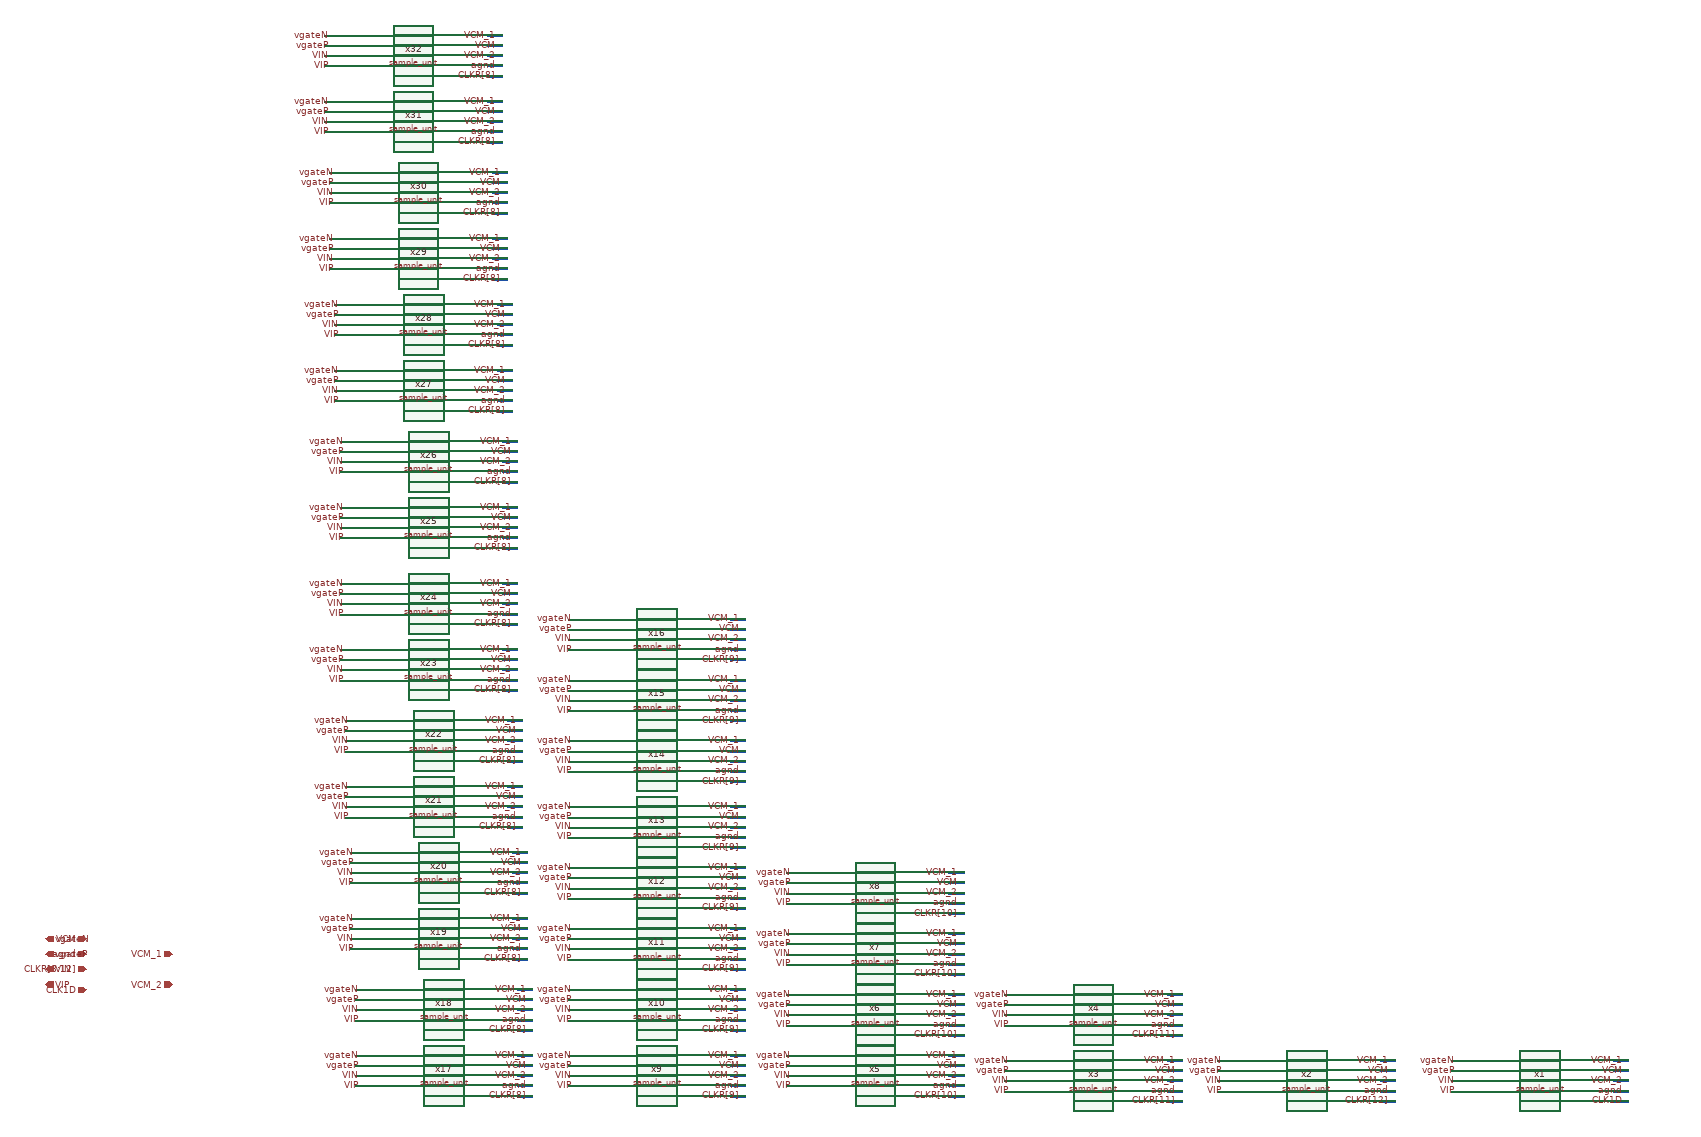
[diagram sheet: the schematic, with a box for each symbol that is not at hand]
v {xschem version=3.1.0 file_version=1.2
}
G {}
K {}
V {}
S {}
E {}
N 200 -80 220 -80 {
lab=VIN}
N 200 -60 220 -60 {
lab=VIP}
N 200 -100 220 -100 {
lab=vgateP}
N 200 -120 220 -120 {
lab=vgateN}
N 520 -120 550 -120 {
lab=VCM_1}
N 520 -100 550 -100 {
lab=VCM}
N 520 -80 550 -80 {
lab=VCM_2}
N 520 -40 550 -40 {
lab=CLK1D}
N 520 -60 550 -60 {
lab=agnd}
N -260 -80 -240 -80 {
lab=VIN}
N -260 -60 -240 -60 {
lab=VIP}
N -260 -100 -240 -100 {
lab=vgateP}
N -260 -120 -240 -120 {
lab=vgateN}
N 60 -120 90 -120 {
lab=VCM_1}
N 60 -100 90 -100 {
lab=VCM}
N 60 -80 90 -80 {
lab=VCM_2}
N 60 -40 90 -40 {
lab=CLKR[12]}
N 60 -60 90 -60 {
lab=agnd}
N -680 -80 -660 -80 {
lab=VIN}
N -680 -60 -660 -60 {
lab=VIP}
N -680 -100 -660 -100 {
lab=vgateP}
N -680 -120 -660 -120 {
lab=vgateN}
N -360 -120 -330 -120 {
lab=VCM_1}
N -360 -100 -330 -100 {
lab=VCM}
N -360 -80 -330 -80 {
lab=VCM_2}
N -360 -40 -330 -40 {
lab=CLKR[11]}
N -360 -60 -330 -60 {
lab=agnd}
N -680 -210 -660 -210 {
lab=VIN}
N -680 -190 -660 -190 {
lab=VIP}
N -680 -230 -660 -230 {
lab=vgateP}
N -680 -250 -660 -250 {
lab=vgateN}
N -360 -250 -330 -250 {
lab=VCM_1}
N -360 -230 -330 -230 {
lab=VCM}
N -360 -210 -330 -210 {
lab=VCM_2}
N -360 -170 -330 -170 {
lab=CLKR[11]}
N -360 -190 -330 -190 {
lab=agnd}
N -1110 -90 -1090 -90 {
lab=VIN}
N -1110 -70 -1090 -70 {
lab=VIP}
N -1110 -110 -1090 -110 {
lab=vgateP}
N -1110 -130 -1090 -130 {
lab=vgateN}
N -790 -130 -760 -130 {
lab=VCM_1}
N -790 -110 -760 -110 {
lab=VCM}
N -790 -90 -760 -90 {
lab=VCM_2}
N -790 -50 -760 -50 {
lab=CLKR[10]}
N -790 -70 -760 -70 {
lab=agnd}
N -1110 -210 -1090 -210 {
lab=VIN}
N -1110 -190 -1090 -190 {
lab=VIP}
N -1110 -230 -1090 -230 {
lab=vgateP}
N -1110 -250 -1090 -250 {
lab=vgateN}
N -790 -250 -760 -250 {
lab=VCM_1}
N -790 -230 -760 -230 {
lab=VCM}
N -790 -210 -760 -210 {
lab=VCM_2}
N -790 -170 -760 -170 {
lab=CLKR[10]}
N -790 -190 -760 -190 {
lab=agnd}
N -1110 -330 -1090 -330 {
lab=VIN}
N -1110 -310 -1090 -310 {
lab=VIP}
N -1110 -350 -1090 -350 {
lab=vgateP}
N -1110 -370 -1090 -370 {
lab=vgateN}
N -790 -370 -760 -370 {
lab=VCM_1}
N -790 -350 -760 -350 {
lab=VCM}
N -790 -330 -760 -330 {
lab=VCM_2}
N -790 -290 -760 -290 {
lab=CLKR[10]}
N -790 -310 -760 -310 {
lab=agnd}
N -1110 -450 -1090 -450 {
lab=VIN}
N -1110 -430 -1090 -430 {
lab=VIP}
N -1110 -470 -1090 -470 {
lab=vgateP}
N -1110 -490 -1090 -490 {
lab=vgateN}
N -790 -490 -760 -490 {
lab=VCM_1}
N -790 -470 -760 -470 {
lab=VCM}
N -790 -450 -760 -450 {
lab=VCM_2}
N -790 -410 -760 -410 {
lab=CLKR[10]}
N -790 -430 -760 -430 {
lab=agnd}
N -1540 -90 -1520 -90 {
lab=VIN}
N -1540 -70 -1520 -70 {
lab=VIP}
N -1540 -110 -1520 -110 {
lab=vgateP}
N -1540 -130 -1520 -130 {
lab=vgateN}
N -1220 -130 -1190 -130 {
lab=VCM_1}
N -1220 -110 -1190 -110 {
lab=VCM}
N -1220 -90 -1190 -90 {
lab=VCM_2}
N -1220 -50 -1190 -50 {
lab=CLKR[10]}
N -1220 -70 -1190 -70 {
lab=agnd}
N -1540 -220 -1520 -220 {
lab=VIN}
N -1540 -200 -1520 -200 {
lab=VIP}
N -1540 -240 -1520 -240 {
lab=vgateP}
N -1540 -260 -1520 -260 {
lab=vgateN}
N -1220 -260 -1190 -260 {
lab=VCM_1}
N -1220 -240 -1190 -240 {
lab=VCM}
N -1220 -220 -1190 -220 {
lab=VCM_2}
N -1220 -180 -1190 -180 {
lab=CLKR[10]}
N -1220 -200 -1190 -200 {
lab=agnd}
N -1540 -340 -1520 -340 {
lab=VIN}
N -1540 -320 -1520 -320 {
lab=VIP}
N -1540 -360 -1520 -360 {
lab=vgateP}
N -1540 -380 -1520 -380 {
lab=vgateN}
N -1220 -380 -1190 -380 {
lab=VCM_1}
N -1220 -360 -1190 -360 {
lab=VCM}
N -1220 -340 -1190 -340 {
lab=VCM_2}
N -1220 -300 -1190 -300 {
lab=CLKR[10]}
N -1220 -320 -1190 -320 {
lab=agnd}
N -1540 -460 -1520 -460 {
lab=VIN}
N -1540 -440 -1520 -440 {
lab=VIP}
N -1540 -480 -1520 -480 {
lab=vgateP}
N -1540 -500 -1520 -500 {
lab=vgateN}
N -1220 -500 -1190 -500 {
lab=VCM_1}
N -1220 -480 -1190 -480 {
lab=VCM}
N -1220 -460 -1190 -460 {
lab=VCM_2}
N -1220 -420 -1190 -420 {
lab=CLKR[10]}
N -1220 -440 -1190 -440 {
lab=agnd}
N -1540 -580 -1520 -580 {
lab=VIN}
N -1540 -560 -1520 -560 {
lab=VIP}
N -1540 -600 -1520 -600 {
lab=vgateP}
N -1540 -620 -1520 -620 {
lab=vgateN}
N -1220 -620 -1190 -620 {
lab=VCM_1}
N -1220 -600 -1190 -600 {
lab=VCM}
N -1220 -580 -1190 -580 {
lab=VCM_2}
N -1220 -540 -1190 -540 {
lab=CLKR[10]}
N -1220 -560 -1190 -560 {
lab=agnd}
N -1540 -710 -1520 -710 {
lab=VIN}
N -1540 -690 -1520 -690 {
lab=VIP}
N -1540 -730 -1520 -730 {
lab=vgateP}
N -1540 -750 -1520 -750 {
lab=vgateN}
N -1220 -750 -1190 -750 {
lab=VCM_1}
N -1220 -730 -1190 -730 {
lab=VCM}
N -1220 -710 -1190 -710 {
lab=VCM_2}
N -1220 -670 -1190 -670 {
lab=CLKR[10]}
N -1220 -690 -1190 -690 {
lab=agnd}
N -1540 -830 -1520 -830 {
lab=VIN}
N -1540 -810 -1520 -810 {
lab=VIP}
N -1540 -850 -1520 -850 {
lab=vgateP}
N -1540 -870 -1520 -870 {
lab=vgateN}
N -1220 -870 -1190 -870 {
lab=VCM_1}
N -1220 -850 -1190 -850 {
lab=VCM}
N -1220 -830 -1190 -830 {
lab=VCM_2}
N -1220 -790 -1190 -790 {
lab=CLKR[10]}
N -1220 -810 -1190 -810 {
lab=agnd}
N -1540 -950 -1520 -950 {
lab=VIN}
N -1540 -930 -1520 -930 {
lab=VIP}
N -1540 -970 -1520 -970 {
lab=vgateP}
N -1540 -990 -1520 -990 {
lab=vgateN}
N -1220 -990 -1190 -990 {
lab=VCM_1}
N -1220 -970 -1190 -970 {
lab=VCM}
N -1220 -950 -1190 -950 {
lab=VCM_2}
N -1220 -910 -1190 -910 {
lab=CLKR[10]}
N -1220 -930 -1190 -930 {
lab=agnd}
N -1960 -90 -1940 -90 {
lab=VIN}
N -1960 -70 -1940 -70 {
lab=VIP}
N -1960 -110 -1940 -110 {
lab=vgateP}
N -1960 -130 -1940 -130 {
lab=vgateN}
N -1640 -130 -1610 -130 {
lab=VCM_1}
N -1640 -110 -1610 -110 {
lab=VCM}
N -1640 -90 -1610 -90 {
lab=VCM_2}
N -1640 -50 -1610 -50 {
lab=CLKR[10]}
N -1640 -70 -1610 -70 {
lab=agnd}
N -1960 -220 -1940 -220 {
lab=VIN}
N -1960 -200 -1940 -200 {
lab=VIP}
N -1960 -240 -1940 -240 {
lab=vgateP}
N -1960 -260 -1940 -260 {
lab=vgateN}
N -1640 -260 -1610 -260 {
lab=VCM_1}
N -1640 -240 -1610 -240 {
lab=VCM}
N -1640 -220 -1610 -220 {
lab=VCM_2}
N -1640 -180 -1610 -180 {
lab=CLKR[10]}
N -1640 -200 -1610 -200 {
lab=agnd}
N -1970 -360 -1950 -360 {
lab=VIN}
N -1970 -340 -1950 -340 {
lab=VIP}
N -1970 -380 -1950 -380 {
lab=vgateP}
N -1970 -400 -1950 -400 {
lab=vgateN}
N -1650 -400 -1620 -400 {
lab=VCM_1}
N -1650 -380 -1620 -380 {
lab=VCM}
N -1650 -360 -1620 -360 {
lab=VCM_2}
N -1650 -320 -1620 -320 {
lab=CLKR[10]}
N -1650 -340 -1620 -340 {
lab=agnd}
N -1970 -490 -1950 -490 {
lab=VIN}
N -1970 -470 -1950 -470 {
lab=VIP}
N -1970 -510 -1950 -510 {
lab=vgateP}
N -1970 -530 -1950 -530 {
lab=vgateN}
N -1650 -530 -1620 -530 {
lab=VCM_1}
N -1650 -510 -1620 -510 {
lab=VCM}
N -1650 -490 -1620 -490 {
lab=VCM_2}
N -1650 -450 -1620 -450 {
lab=CLKR[10]}
N -1650 -470 -1620 -470 {
lab=agnd}
N -1980 -620 -1960 -620 {
lab=VIN}
N -1980 -600 -1960 -600 {
lab=VIP}
N -1980 -640 -1960 -640 {
lab=vgateP}
N -1980 -660 -1960 -660 {
lab=vgateN}
N -1660 -660 -1630 -660 {
lab=VCM_1}
N -1660 -640 -1630 -640 {
lab=VCM}
N -1660 -620 -1630 -620 {
lab=VCM_2}
N -1660 -580 -1630 -580 {
lab=CLKR[10]}
N -1660 -600 -1630 -600 {
lab=agnd}
N -1980 -750 -1960 -750 {
lab=VIN}
N -1980 -730 -1960 -730 {
lab=VIP}
N -1980 -770 -1960 -770 {
lab=vgateP}
N -1980 -790 -1960 -790 {
lab=vgateN}
N -1660 -790 -1630 -790 {
lab=VCM_1}
N -1660 -770 -1630 -770 {
lab=VCM}
N -1660 -750 -1630 -750 {
lab=VCM_2}
N -1660 -710 -1630 -710 {
lab=CLKR[10]}
N -1660 -730 -1630 -730 {
lab=agnd}
N -1990 -890 -1970 -890 {
lab=VIN}
N -1990 -870 -1970 -870 {
lab=VIP}
N -1990 -910 -1970 -910 {
lab=vgateP}
N -1990 -930 -1970 -930 {
lab=vgateN}
N -1670 -930 -1640 -930 {
lab=VCM_1}
N -1670 -910 -1640 -910 {
lab=VCM}
N -1670 -890 -1640 -890 {
lab=VCM_2}
N -1670 -850 -1640 -850 {
lab=CLKR[10]}
N -1670 -870 -1640 -870 {
lab=agnd}
N -1990 -1020 -1970 -1020 {
lab=VIN}
N -1990 -1000 -1970 -1000 {
lab=VIP}
N -1990 -1040 -1970 -1040 {
lab=vgateP}
N -1990 -1060 -1970 -1060 {
lab=vgateN}
N -1670 -1060 -1640 -1060 {
lab=VCM_1}
N -1670 -1040 -1640 -1040 {
lab=VCM}
N -1670 -1020 -1640 -1020 {
lab=VCM_2}
N -1670 -980 -1640 -980 {
lab=CLKR[10]}
N -1670 -1000 -1640 -1000 {
lab=agnd}
N -1990 -1170 -1970 -1170 {
lab=VIN}
N -1990 -1150 -1970 -1150 {
lab=VIP}
N -1990 -1190 -1970 -1190 {
lab=vgateP}
N -1990 -1210 -1970 -1210 {
lab=vgateN}
N -1670 -1210 -1640 -1210 {
lab=VCM_1}
N -1670 -1190 -1640 -1190 {
lab=VCM}
N -1670 -1170 -1640 -1170 {
lab=VCM_2}
N -1670 -1130 -1640 -1130 {
lab=CLKR[10]}
N -1670 -1150 -1640 -1150 {
lab=agnd}
N -1990 -1300 -1970 -1300 {
lab=VIN}
N -1990 -1280 -1970 -1280 {
lab=VIP}
N -1990 -1320 -1970 -1320 {
lab=vgateP}
N -1990 -1340 -1970 -1340 {
lab=vgateN}
N -1670 -1340 -1640 -1340 {
lab=VCM_1}
N -1670 -1320 -1640 -1320 {
lab=VCM}
N -1670 -1300 -1640 -1300 {
lab=VCM_2}
N -1670 -1260 -1640 -1260 {
lab=CLKR[10]}
N -1670 -1280 -1640 -1280 {
lab=agnd}
N -2000 -1440 -1980 -1440 {
lab=VIN}
N -2000 -1420 -1980 -1420 {
lab=VIP}
N -2000 -1460 -1980 -1460 {
lab=vgateP}
N -2000 -1480 -1980 -1480 {
lab=vgateN}
N -1680 -1480 -1650 -1480 {
lab=VCM_1}
N -1680 -1460 -1650 -1460 {
lab=VCM}
N -1680 -1440 -1650 -1440 {
lab=VCM_2}
N -1680 -1400 -1650 -1400 {
lab=CLKR[10]}
N -1680 -1420 -1650 -1420 {
lab=agnd}
N -2000 -1570 -1980 -1570 {
lab=VIN}
N -2000 -1550 -1980 -1550 {
lab=VIP}
N -2000 -1590 -1980 -1590 {
lab=vgateP}
N -2000 -1610 -1980 -1610 {
lab=vgateN}
N -1680 -1610 -1650 -1610 {
lab=VCM_1}
N -1680 -1590 -1650 -1590 {
lab=VCM}
N -1680 -1570 -1650 -1570 {
lab=VCM_2}
N -1680 -1530 -1650 -1530 {
lab=CLKR[10]}
N -1680 -1550 -1650 -1550 {
lab=agnd}
N -2010 -1700 -1990 -1700 {
lab=VIN}
N -2010 -1680 -1990 -1680 {
lab=VIP}
N -2010 -1720 -1990 -1720 {
lab=vgateP}
N -2010 -1740 -1990 -1740 {
lab=vgateN}
N -1690 -1740 -1660 -1740 {
lab=VCM_1}
N -1690 -1720 -1660 -1720 {
lab=VCM}
N -1690 -1700 -1660 -1700 {
lab=VCM_2}
N -1690 -1660 -1660 -1660 {
lab=CLKR[10]}
N -1690 -1680 -1660 -1680 {
lab=agnd}
N -2010 -1830 -1990 -1830 {
lab=VIN}
N -2010 -1810 -1990 -1810 {
lab=VIP}
N -2010 -1850 -1990 -1850 {
lab=vgateP}
N -2010 -1870 -1990 -1870 {
lab=vgateN}
N -1690 -1870 -1660 -1870 {
lab=VCM_1}
N -1690 -1850 -1660 -1850 {
lab=VCM}
N -1690 -1830 -1660 -1830 {
lab=VCM_2}
N -1690 -1790 -1660 -1790 {
lab=CLKR[10]}
N -1690 -1810 -1660 -1810 {
lab=agnd}
N -2020 -1970 -2000 -1970 {
lab=VIN}
N -2020 -1950 -2000 -1950 {
lab=VIP}
N -2020 -1990 -2000 -1990 {
lab=vgateP}
N -2020 -2010 -2000 -2010 {
lab=vgateN}
N -1700 -2010 -1670 -2010 {
lab=VCM_1}
N -1700 -1990 -1670 -1990 {
lab=VCM}
N -1700 -1970 -1670 -1970 {
lab=VCM_2}
N -1700 -1930 -1670 -1930 {
lab=CLKR[10]}
N -1700 -1950 -1670 -1950 {
lab=agnd}
N -2020 -2100 -2000 -2100 {
lab=VIN}
N -2020 -2080 -2000 -2080 {
lab=VIP}
N -2020 -2120 -2000 -2120 {
lab=vgateP}
N -2020 -2140 -2000 -2140 {
lab=vgateN}
N -1700 -2140 -1670 -2140 {
lab=VCM_1}
N -1700 -2120 -1670 -2120 {
lab=VCM}
N -1700 -2100 -1670 -2100 {
lab=VCM_2}
N -1700 -2060 -1670 -2060 {
lab=CLKR[10]}
N -1700 -2080 -1670 -2080 {
lab=agnd}
C {/home/yihengfu/openmpw/tools-dev/sample_unit.sym} 370 -80 0 0 {name=x1}
C {lab_pin.sym} 540 -120 0 0 {name=p1 sig_type=std_logic lab=VCM_1}
C {lab_pin.sym} 540 -100 0 0 {name=p2 sig_type=std_logic lab=VCM}
C {lab_pin.sym} 540 -80 0 0 {name=p3 sig_type=std_logic lab=VCM_2}
C {lab_pin.sym} 540 -60 0 0 {name=p4 sig_type=std_logic lab=agnd}
C {lab_pin.sym} 540 -40 0 0 {name=p5 sig_type=std_logic lab=CLK1D}
C {lab_pin.sym} 210 -120 0 0 {name=p6 sig_type=std_logic lab=vgateN}
C {lab_pin.sym} 210 -100 0 0 {name=p7 sig_type=std_logic lab=vgateP}
C {lab_pin.sym} 210 -80 0 0 {name=p8 sig_type=std_logic lab=VIN}
C {lab_pin.sym} 210 -60 0 0 {name=p9 sig_type=std_logic lab=VIP}
C {/home/yihengfu/openmpw/tools-dev/sample_unit.sym} -90 -80 0 0 {name=x2}
C {lab_pin.sym} 80 -120 0 0 {name=p10 sig_type=std_logic lab=VCM_1}
C {lab_pin.sym} 80 -100 0 0 {name=p11 sig_type=std_logic lab=VCM}
C {lab_pin.sym} 80 -80 0 0 {name=p12 sig_type=std_logic lab=VCM_2}
C {lab_pin.sym} 80 -60 0 0 {name=p13 sig_type=std_logic lab=agnd}
C {lab_pin.sym} 80 -40 0 0 {name=p14 sig_type=std_logic lab=CLKR[12]}
C {lab_pin.sym} -250 -120 0 0 {name=p15 sig_type=std_logic lab=vgateN}
C {lab_pin.sym} -250 -100 0 0 {name=p16 sig_type=std_logic lab=vgateP}
C {lab_pin.sym} -250 -80 0 0 {name=p17 sig_type=std_logic lab=VIN}
C {lab_pin.sym} -250 -60 0 0 {name=p18 sig_type=std_logic lab=VIP}
C {/home/yihengfu/openmpw/tools-dev/sample_unit.sym} -510 -80 0 0 {name=x3}
C {lab_pin.sym} -340 -120 0 0 {name=p19 sig_type=std_logic lab=VCM_1}
C {lab_pin.sym} -340 -100 0 0 {name=p20 sig_type=std_logic lab=VCM}
C {lab_pin.sym} -340 -80 0 0 {name=p21 sig_type=std_logic lab=VCM_2}
C {lab_pin.sym} -340 -60 0 0 {name=p22 sig_type=std_logic lab=agnd}
C {lab_pin.sym} -340 -40 0 0 {name=p23 sig_type=std_logic lab=CLKR[11]}
C {lab_pin.sym} -670 -120 0 0 {name=p24 sig_type=std_logic lab=vgateN}
C {lab_pin.sym} -670 -100 0 0 {name=p25 sig_type=std_logic lab=vgateP}
C {lab_pin.sym} -670 -80 0 0 {name=p26 sig_type=std_logic lab=VIN}
C {lab_pin.sym} -670 -60 0 0 {name=p27 sig_type=std_logic lab=VIP}
C {/home/yihengfu/openmpw/tools-dev/sample_unit.sym} -510 -210 0 0 {name=x4}
C {lab_pin.sym} -340 -250 0 0 {name=p28 sig_type=std_logic lab=VCM_1}
C {lab_pin.sym} -340 -230 0 0 {name=p29 sig_type=std_logic lab=VCM}
C {lab_pin.sym} -340 -210 0 0 {name=p30 sig_type=std_logic lab=VCM_2}
C {lab_pin.sym} -340 -190 0 0 {name=p31 sig_type=std_logic lab=agnd}
C {lab_pin.sym} -340 -170 0 0 {name=p32 sig_type=std_logic lab=CLKR[11]}
C {lab_pin.sym} -670 -250 0 0 {name=p33 sig_type=std_logic lab=vgateN}
C {lab_pin.sym} -670 -230 0 0 {name=p34 sig_type=std_logic lab=vgateP}
C {lab_pin.sym} -670 -210 0 0 {name=p35 sig_type=std_logic lab=VIN}
C {lab_pin.sym} -670 -190 0 0 {name=p36 sig_type=std_logic lab=VIP}
C {/home/yihengfu/openmpw/tools-dev/sample_unit.sym} -940 -90 0 0 {name=x5}
C {lab_pin.sym} -770 -130 0 0 {name=p37 sig_type=std_logic lab=VCM_1}
C {lab_pin.sym} -770 -110 0 0 {name=p38 sig_type=std_logic lab=VCM}
C {lab_pin.sym} -770 -90 0 0 {name=p39 sig_type=std_logic lab=VCM_2}
C {lab_pin.sym} -770 -70 0 0 {name=p40 sig_type=std_logic lab=agnd}
C {lab_pin.sym} -770 -50 0 0 {name=p41 sig_type=std_logic lab=CLKR[10]}
C {lab_pin.sym} -1100 -130 0 0 {name=p42 sig_type=std_logic lab=vgateN}
C {lab_pin.sym} -1100 -110 0 0 {name=p43 sig_type=std_logic lab=vgateP}
C {lab_pin.sym} -1100 -90 0 0 {name=p44 sig_type=std_logic lab=VIN}
C {lab_pin.sym} -1100 -70 0 0 {name=p45 sig_type=std_logic lab=VIP}
C {/home/yihengfu/openmpw/tools-dev/sample_unit.sym} -940 -210 0 0 {name=x6}
C {lab_pin.sym} -770 -250 0 0 {name=p46 sig_type=std_logic lab=VCM_1}
C {lab_pin.sym} -770 -230 0 0 {name=p47 sig_type=std_logic lab=VCM}
C {lab_pin.sym} -770 -210 0 0 {name=p48 sig_type=std_logic lab=VCM_2}
C {lab_pin.sym} -770 -190 0 0 {name=p49 sig_type=std_logic lab=agnd}
C {lab_pin.sym} -770 -170 0 0 {name=p50 sig_type=std_logic lab=CLKR[10]}
C {lab_pin.sym} -1100 -250 0 0 {name=p51 sig_type=std_logic lab=vgateN}
C {lab_pin.sym} -1100 -230 0 0 {name=p52 sig_type=std_logic lab=vgateP}
C {lab_pin.sym} -1100 -210 0 0 {name=p53 sig_type=std_logic lab=VIN}
C {lab_pin.sym} -1100 -190 0 0 {name=p54 sig_type=std_logic lab=VIP}
C {/home/yihengfu/openmpw/tools-dev/sample_unit.sym} -940 -330 0 0 {name=x7}
C {lab_pin.sym} -770 -370 0 0 {name=p55 sig_type=std_logic lab=VCM_1}
C {lab_pin.sym} -770 -350 0 0 {name=p56 sig_type=std_logic lab=VCM}
C {lab_pin.sym} -770 -330 0 0 {name=p57 sig_type=std_logic lab=VCM_2}
C {lab_pin.sym} -770 -310 0 0 {name=p58 sig_type=std_logic lab=agnd}
C {lab_pin.sym} -770 -290 0 0 {name=p59 sig_type=std_logic lab=CLKR[10]}
C {lab_pin.sym} -1100 -370 0 0 {name=p60 sig_type=std_logic lab=vgateN}
C {lab_pin.sym} -1100 -350 0 0 {name=p61 sig_type=std_logic lab=vgateP}
C {lab_pin.sym} -1100 -330 0 0 {name=p62 sig_type=std_logic lab=VIN}
C {lab_pin.sym} -1100 -310 0 0 {name=p63 sig_type=std_logic lab=VIP}
C {/home/yihengfu/openmpw/tools-dev/sample_unit.sym} -940 -450 0 0 {name=x8}
C {lab_pin.sym} -770 -490 0 0 {name=p64 sig_type=std_logic lab=VCM_1}
C {lab_pin.sym} -770 -470 0 0 {name=p65 sig_type=std_logic lab=VCM}
C {lab_pin.sym} -770 -450 0 0 {name=p66 sig_type=std_logic lab=VCM_2}
C {lab_pin.sym} -770 -430 0 0 {name=p67 sig_type=std_logic lab=agnd}
C {lab_pin.sym} -770 -410 0 0 {name=p68 sig_type=std_logic lab=CLKR[10]}
C {lab_pin.sym} -1100 -490 0 0 {name=p69 sig_type=std_logic lab=vgateN}
C {lab_pin.sym} -1100 -470 0 0 {name=p70 sig_type=std_logic lab=vgateP}
C {lab_pin.sym} -1100 -450 0 0 {name=p71 sig_type=std_logic lab=VIN}
C {lab_pin.sym} -1100 -430 0 0 {name=p72 sig_type=std_logic lab=VIP}
C {/home/yihengfu/openmpw/tools-dev/sample_unit.sym} -1370 -90 0 0 {name=x9}
C {lab_pin.sym} -1200 -130 0 0 {name=p73 sig_type=std_logic lab=VCM_1}
C {lab_pin.sym} -1200 -110 0 0 {name=p74 sig_type=std_logic lab=VCM}
C {lab_pin.sym} -1200 -90 0 0 {name=p75 sig_type=std_logic lab=VCM_2}
C {lab_pin.sym} -1200 -70 0 0 {name=p76 sig_type=std_logic lab=agnd}
C {lab_pin.sym} -1200 -50 0 0 {name=p77 sig_type=std_logic lab=CLKR[9]}
C {lab_pin.sym} -1530 -130 0 0 {name=p78 sig_type=std_logic lab=vgateN}
C {lab_pin.sym} -1530 -110 0 0 {name=p79 sig_type=std_logic lab=vgateP}
C {lab_pin.sym} -1530 -90 0 0 {name=p80 sig_type=std_logic lab=VIN}
C {lab_pin.sym} -1530 -70 0 0 {name=p81 sig_type=std_logic lab=VIP}
C {/home/yihengfu/openmpw/tools-dev/sample_unit.sym} -1370 -220 0 0 {name=x10}
C {lab_pin.sym} -1200 -260 0 0 {name=p82 sig_type=std_logic lab=VCM_1}
C {lab_pin.sym} -1200 -240 0 0 {name=p83 sig_type=std_logic lab=VCM}
C {lab_pin.sym} -1200 -220 0 0 {name=p84 sig_type=std_logic lab=VCM_2}
C {lab_pin.sym} -1200 -200 0 0 {name=p85 sig_type=std_logic lab=agnd}
C {lab_pin.sym} -1200 -180 0 0 {name=p86 sig_type=std_logic lab=CLKR[9]}
C {lab_pin.sym} -1530 -260 0 0 {name=p87 sig_type=std_logic lab=vgateN}
C {lab_pin.sym} -1530 -240 0 0 {name=p88 sig_type=std_logic lab=vgateP}
C {lab_pin.sym} -1530 -220 0 0 {name=p89 sig_type=std_logic lab=VIN}
C {lab_pin.sym} -1530 -200 0 0 {name=p90 sig_type=std_logic lab=VIP}
C {/home/yihengfu/openmpw/tools-dev/sample_unit.sym} -1370 -340 0 0 {name=x11}
C {lab_pin.sym} -1200 -380 0 0 {name=p91 sig_type=std_logic lab=VCM_1}
C {lab_pin.sym} -1200 -360 0 0 {name=p92 sig_type=std_logic lab=VCM}
C {lab_pin.sym} -1200 -340 0 0 {name=p93 sig_type=std_logic lab=VCM_2}
C {lab_pin.sym} -1200 -320 0 0 {name=p94 sig_type=std_logic lab=agnd}
C {lab_pin.sym} -1200 -300 0 0 {name=p95 sig_type=std_logic lab=CLKR[9]}
C {lab_pin.sym} -1530 -380 0 0 {name=p96 sig_type=std_logic lab=vgateN}
C {lab_pin.sym} -1530 -360 0 0 {name=p97 sig_type=std_logic lab=vgateP}
C {lab_pin.sym} -1530 -340 0 0 {name=p98 sig_type=std_logic lab=VIN}
C {lab_pin.sym} -1530 -320 0 0 {name=p99 sig_type=std_logic lab=VIP}
C {/home/yihengfu/openmpw/tools-dev/sample_unit.sym} -1370 -460 0 0 {name=x12}
C {lab_pin.sym} -1200 -500 0 0 {name=p100 sig_type=std_logic lab=VCM_1}
C {lab_pin.sym} -1200 -480 0 0 {name=p101 sig_type=std_logic lab=VCM}
C {lab_pin.sym} -1200 -460 0 0 {name=p102 sig_type=std_logic lab=VCM_2}
C {lab_pin.sym} -1200 -440 0 0 {name=p103 sig_type=std_logic lab=agnd}
C {lab_pin.sym} -1200 -420 0 0 {name=p104 sig_type=std_logic lab=CLKR[9]}
C {lab_pin.sym} -1530 -500 0 0 {name=p105 sig_type=std_logic lab=vgateN}
C {lab_pin.sym} -1530 -480 0 0 {name=p106 sig_type=std_logic lab=vgateP}
C {lab_pin.sym} -1530 -460 0 0 {name=p107 sig_type=std_logic lab=VIN}
C {lab_pin.sym} -1530 -440 0 0 {name=p108 sig_type=std_logic lab=VIP}
C {/home/yihengfu/openmpw/tools-dev/sample_unit.sym} -1370 -580 0 0 {name=x13}
C {lab_pin.sym} -1200 -620 0 0 {name=p109 sig_type=std_logic lab=VCM_1}
C {lab_pin.sym} -1200 -600 0 0 {name=p110 sig_type=std_logic lab=VCM}
C {lab_pin.sym} -1200 -580 0 0 {name=p111 sig_type=std_logic lab=VCM_2}
C {lab_pin.sym} -1200 -560 0 0 {name=p112 sig_type=std_logic lab=agnd}
C {lab_pin.sym} -1200 -540 0 0 {name=p113 sig_type=std_logic lab=CLKR[9]}
C {lab_pin.sym} -1530 -620 0 0 {name=p114 sig_type=std_logic lab=vgateN}
C {lab_pin.sym} -1530 -600 0 0 {name=p115 sig_type=std_logic lab=vgateP}
C {lab_pin.sym} -1530 -580 0 0 {name=p116 sig_type=std_logic lab=VIN}
C {lab_pin.sym} -1530 -560 0 0 {name=p117 sig_type=std_logic lab=VIP}
C {/home/yihengfu/openmpw/tools-dev/sample_unit.sym} -1370 -710 0 0 {name=x14}
C {lab_pin.sym} -1200 -750 0 0 {name=p118 sig_type=std_logic lab=VCM_1}
C {lab_pin.sym} -1200 -730 0 0 {name=p119 sig_type=std_logic lab=VCM}
C {lab_pin.sym} -1200 -710 0 0 {name=p120 sig_type=std_logic lab=VCM_2}
C {lab_pin.sym} -1200 -690 0 0 {name=p121 sig_type=std_logic lab=agnd}
C {lab_pin.sym} -1200 -670 0 0 {name=p122 sig_type=std_logic lab=CLKR[9]}
C {lab_pin.sym} -1530 -750 0 0 {name=p123 sig_type=std_logic lab=vgateN}
C {lab_pin.sym} -1530 -730 0 0 {name=p124 sig_type=std_logic lab=vgateP}
C {lab_pin.sym} -1530 -710 0 0 {name=p125 sig_type=std_logic lab=VIN}
C {lab_pin.sym} -1530 -690 0 0 {name=p126 sig_type=std_logic lab=VIP}
C {/home/yihengfu/openmpw/tools-dev/sample_unit.sym} -1370 -830 0 0 {name=x15}
C {lab_pin.sym} -1200 -870 0 0 {name=p127 sig_type=std_logic lab=VCM_1}
C {lab_pin.sym} -1200 -850 0 0 {name=p128 sig_type=std_logic lab=VCM}
C {lab_pin.sym} -1200 -830 0 0 {name=p129 sig_type=std_logic lab=VCM_2}
C {lab_pin.sym} -1200 -810 0 0 {name=p130 sig_type=std_logic lab=agnd}
C {lab_pin.sym} -1200 -790 0 0 {name=p131 sig_type=std_logic lab=CLKR[9]}
C {lab_pin.sym} -1530 -870 0 0 {name=p132 sig_type=std_logic lab=vgateN}
C {lab_pin.sym} -1530 -850 0 0 {name=p133 sig_type=std_logic lab=vgateP}
C {lab_pin.sym} -1530 -830 0 0 {name=p134 sig_type=std_logic lab=VIN}
C {lab_pin.sym} -1530 -810 0 0 {name=p135 sig_type=std_logic lab=VIP}
C {/home/yihengfu/openmpw/tools-dev/sample_unit.sym} -1370 -950 0 0 {name=x16}
C {lab_pin.sym} -1200 -990 0 0 {name=p136 sig_type=std_logic lab=VCM_1}
C {lab_pin.sym} -1200 -970 0 0 {name=p137 sig_type=std_logic lab=VCM}
C {lab_pin.sym} -1200 -950 0 0 {name=p138 sig_type=std_logic lab=VCM_2}
C {lab_pin.sym} -1200 -930 0 0 {name=p139 sig_type=std_logic lab=agnd}
C {lab_pin.sym} -1200 -910 0 0 {name=p140 sig_type=std_logic lab=CLKR[9]}
C {lab_pin.sym} -1530 -990 0 0 {name=p141 sig_type=std_logic lab=vgateN}
C {lab_pin.sym} -1530 -970 0 0 {name=p142 sig_type=std_logic lab=vgateP}
C {lab_pin.sym} -1530 -950 0 0 {name=p143 sig_type=std_logic lab=VIN}
C {lab_pin.sym} -1530 -930 0 0 {name=p144 sig_type=std_logic lab=VIP}
C {/home/yihengfu/openmpw/tools-dev/sample_unit.sym} -1790 -90 0 0 {name=x17}
C {lab_pin.sym} -1620 -130 0 0 {name=p145 sig_type=std_logic lab=VCM_1}
C {lab_pin.sym} -1620 -110 0 0 {name=p146 sig_type=std_logic lab=VCM}
C {lab_pin.sym} -1620 -90 0 0 {name=p147 sig_type=std_logic lab=VCM_2}
C {lab_pin.sym} -1620 -70 0 0 {name=p148 sig_type=std_logic lab=agnd}
C {lab_pin.sym} -1620 -50 0 0 {name=p149 sig_type=std_logic lab=CLKR[8]}
C {lab_pin.sym} -1950 -130 0 0 {name=p150 sig_type=std_logic lab=vgateN}
C {lab_pin.sym} -1950 -110 0 0 {name=p151 sig_type=std_logic lab=vgateP}
C {lab_pin.sym} -1950 -90 0 0 {name=p152 sig_type=std_logic lab=VIN}
C {lab_pin.sym} -1950 -70 0 0 {name=p153 sig_type=std_logic lab=VIP}
C {/home/yihengfu/openmpw/tools-dev/sample_unit.sym} -1790 -220 0 0 {name=x18}
C {lab_pin.sym} -1620 -260 0 0 {name=p154 sig_type=std_logic lab=VCM_1}
C {lab_pin.sym} -1620 -240 0 0 {name=p155 sig_type=std_logic lab=VCM}
C {lab_pin.sym} -1620 -220 0 0 {name=p156 sig_type=std_logic lab=VCM_2}
C {lab_pin.sym} -1620 -200 0 0 {name=p157 sig_type=std_logic lab=agnd}
C {lab_pin.sym} -1620 -180 0 0 {name=p158 sig_type=std_logic lab=CLKR[8]}
C {lab_pin.sym} -1950 -260 0 0 {name=p159 sig_type=std_logic lab=vgateN}
C {lab_pin.sym} -1950 -240 0 0 {name=p160 sig_type=std_logic lab=vgateP}
C {lab_pin.sym} -1950 -220 0 0 {name=p161 sig_type=std_logic lab=VIN}
C {lab_pin.sym} -1950 -200 0 0 {name=p162 sig_type=std_logic lab=VIP}
C {/home/yihengfu/openmpw/tools-dev/sample_unit.sym} -1800 -360 0 0 {name=x19}
C {lab_pin.sym} -1630 -400 0 0 {name=p163 sig_type=std_logic lab=VCM_1}
C {lab_pin.sym} -1630 -380 0 0 {name=p164 sig_type=std_logic lab=VCM}
C {lab_pin.sym} -1630 -360 0 0 {name=p165 sig_type=std_logic lab=VCM_2}
C {lab_pin.sym} -1630 -340 0 0 {name=p166 sig_type=std_logic lab=agnd}
C {lab_pin.sym} -1630 -320 0 0 {name=p167 sig_type=std_logic lab=CLKR[8]}
C {lab_pin.sym} -1960 -400 0 0 {name=p168 sig_type=std_logic lab=vgateN}
C {lab_pin.sym} -1960 -380 0 0 {name=p169 sig_type=std_logic lab=vgateP}
C {lab_pin.sym} -1960 -360 0 0 {name=p170 sig_type=std_logic lab=VIN}
C {lab_pin.sym} -1960 -340 0 0 {name=p171 sig_type=std_logic lab=VIP}
C {/home/yihengfu/openmpw/tools-dev/sample_unit.sym} -1800 -490 0 0 {name=x20}
C {lab_pin.sym} -1630 -530 0 0 {name=p172 sig_type=std_logic lab=VCM_1}
C {lab_pin.sym} -1630 -510 0 0 {name=p173 sig_type=std_logic lab=VCM}
C {lab_pin.sym} -1630 -490 0 0 {name=p174 sig_type=std_logic lab=VCM_2}
C {lab_pin.sym} -1630 -470 0 0 {name=p175 sig_type=std_logic lab=agnd}
C {lab_pin.sym} -1630 -450 0 0 {name=p176 sig_type=std_logic lab=CLKR[8]}
C {lab_pin.sym} -1960 -530 0 0 {name=p177 sig_type=std_logic lab=vgateN}
C {lab_pin.sym} -1960 -510 0 0 {name=p178 sig_type=std_logic lab=vgateP}
C {lab_pin.sym} -1960 -490 0 0 {name=p179 sig_type=std_logic lab=VIN}
C {lab_pin.sym} -1960 -470 0 0 {name=p180 sig_type=std_logic lab=VIP}
C {/home/yihengfu/openmpw/tools-dev/sample_unit.sym} -1810 -620 0 0 {name=x21}
C {lab_pin.sym} -1640 -660 0 0 {name=p181 sig_type=std_logic lab=VCM_1}
C {lab_pin.sym} -1640 -640 0 0 {name=p182 sig_type=std_logic lab=VCM}
C {lab_pin.sym} -1640 -620 0 0 {name=p183 sig_type=std_logic lab=VCM_2}
C {lab_pin.sym} -1640 -600 0 0 {name=p184 sig_type=std_logic lab=agnd}
C {lab_pin.sym} -1640 -580 0 0 {name=p185 sig_type=std_logic lab=CLKR[8]}
C {lab_pin.sym} -1970 -660 0 0 {name=p186 sig_type=std_logic lab=vgateN}
C {lab_pin.sym} -1970 -640 0 0 {name=p187 sig_type=std_logic lab=vgateP}
C {lab_pin.sym} -1970 -620 0 0 {name=p188 sig_type=std_logic lab=VIN}
C {lab_pin.sym} -1970 -600 0 0 {name=p189 sig_type=std_logic lab=VIP}
C {/home/yihengfu/openmpw/tools-dev/sample_unit.sym} -1810 -750 0 0 {name=x22}
C {lab_pin.sym} -1640 -790 0 0 {name=p190 sig_type=std_logic lab=VCM_1}
C {lab_pin.sym} -1640 -770 0 0 {name=p191 sig_type=std_logic lab=VCM}
C {lab_pin.sym} -1640 -750 0 0 {name=p192 sig_type=std_logic lab=VCM_2}
C {lab_pin.sym} -1640 -730 0 0 {name=p193 sig_type=std_logic lab=agnd}
C {lab_pin.sym} -1640 -710 0 0 {name=p194 sig_type=std_logic lab=CLKR[8]}
C {lab_pin.sym} -1970 -790 0 0 {name=p195 sig_type=std_logic lab=vgateN}
C {lab_pin.sym} -1970 -770 0 0 {name=p196 sig_type=std_logic lab=vgateP}
C {lab_pin.sym} -1970 -750 0 0 {name=p197 sig_type=std_logic lab=VIN}
C {lab_pin.sym} -1970 -730 0 0 {name=p198 sig_type=std_logic lab=VIP}
C {/home/yihengfu/openmpw/tools-dev/sample_unit.sym} -1820 -890 0 0 {name=x23}
C {lab_pin.sym} -1650 -930 0 0 {name=p199 sig_type=std_logic lab=VCM_1}
C {lab_pin.sym} -1650 -910 0 0 {name=p200 sig_type=std_logic lab=VCM}
C {lab_pin.sym} -1650 -890 0 0 {name=p201 sig_type=std_logic lab=VCM_2}
C {lab_pin.sym} -1650 -870 0 0 {name=p202 sig_type=std_logic lab=agnd}
C {lab_pin.sym} -1650 -850 0 0 {name=p203 sig_type=std_logic lab=CLKR[8]}
C {lab_pin.sym} -1980 -930 0 0 {name=p204 sig_type=std_logic lab=vgateN}
C {lab_pin.sym} -1980 -910 0 0 {name=p205 sig_type=std_logic lab=vgateP}
C {lab_pin.sym} -1980 -890 0 0 {name=p206 sig_type=std_logic lab=VIN}
C {lab_pin.sym} -1980 -870 0 0 {name=p207 sig_type=std_logic lab=VIP}
C {/home/yihengfu/openmpw/tools-dev/sample_unit.sym} -1820 -1020 0 0 {name=x24}
C {lab_pin.sym} -1650 -1060 0 0 {name=p208 sig_type=std_logic lab=VCM_1}
C {lab_pin.sym} -1650 -1040 0 0 {name=p209 sig_type=std_logic lab=VCM}
C {lab_pin.sym} -1650 -1020 0 0 {name=p210 sig_type=std_logic lab=VCM_2}
C {lab_pin.sym} -1650 -1000 0 0 {name=p211 sig_type=std_logic lab=agnd}
C {lab_pin.sym} -1650 -980 0 0 {name=p212 sig_type=std_logic lab=CLKR[8]}
C {lab_pin.sym} -1980 -1060 0 0 {name=p213 sig_type=std_logic lab=vgateN}
C {lab_pin.sym} -1980 -1040 0 0 {name=p214 sig_type=std_logic lab=vgateP}
C {lab_pin.sym} -1980 -1020 0 0 {name=p215 sig_type=std_logic lab=VIN}
C {lab_pin.sym} -1980 -1000 0 0 {name=p216 sig_type=std_logic lab=VIP}
C {/home/yihengfu/openmpw/tools-dev/sample_unit.sym} -1820 -1170 0 0 {name=x25}
C {lab_pin.sym} -1650 -1210 0 0 {name=p217 sig_type=std_logic lab=VCM_1}
C {lab_pin.sym} -1650 -1190 0 0 {name=p218 sig_type=std_logic lab=VCM}
C {lab_pin.sym} -1650 -1170 0 0 {name=p219 sig_type=std_logic lab=VCM_2}
C {lab_pin.sym} -1650 -1150 0 0 {name=p220 sig_type=std_logic lab=agnd}
C {lab_pin.sym} -1650 -1130 0 0 {name=p221 sig_type=std_logic lab=CLKR[8]}
C {lab_pin.sym} -1980 -1210 0 0 {name=p222 sig_type=std_logic lab=vgateN}
C {lab_pin.sym} -1980 -1190 0 0 {name=p223 sig_type=std_logic lab=vgateP}
C {lab_pin.sym} -1980 -1170 0 0 {name=p224 sig_type=std_logic lab=VIN}
C {lab_pin.sym} -1980 -1150 0 0 {name=p225 sig_type=std_logic lab=VIP}
C {/home/yihengfu/openmpw/tools-dev/sample_unit.sym} -1820 -1300 0 0 {name=x26}
C {lab_pin.sym} -1650 -1340 0 0 {name=p226 sig_type=std_logic lab=VCM_1}
C {lab_pin.sym} -1650 -1320 0 0 {name=p227 sig_type=std_logic lab=VCM}
C {lab_pin.sym} -1650 -1300 0 0 {name=p228 sig_type=std_logic lab=VCM_2}
C {lab_pin.sym} -1650 -1280 0 0 {name=p229 sig_type=std_logic lab=agnd}
C {lab_pin.sym} -1650 -1260 0 0 {name=p230 sig_type=std_logic lab=CLKR[8]}
C {lab_pin.sym} -1980 -1340 0 0 {name=p231 sig_type=std_logic lab=vgateN}
C {lab_pin.sym} -1980 -1320 0 0 {name=p232 sig_type=std_logic lab=vgateP}
C {lab_pin.sym} -1980 -1300 0 0 {name=p233 sig_type=std_logic lab=VIN}
C {lab_pin.sym} -1980 -1280 0 0 {name=p234 sig_type=std_logic lab=VIP}
C {/home/yihengfu/openmpw/tools-dev/sample_unit.sym} -1830 -1440 0 0 {name=x27}
C {lab_pin.sym} -1660 -1480 0 0 {name=p235 sig_type=std_logic lab=VCM_1}
C {lab_pin.sym} -1660 -1460 0 0 {name=p236 sig_type=std_logic lab=VCM}
C {lab_pin.sym} -1660 -1440 0 0 {name=p237 sig_type=std_logic lab=VCM_2}
C {lab_pin.sym} -1660 -1420 0 0 {name=p238 sig_type=std_logic lab=agnd}
C {lab_pin.sym} -1660 -1400 0 0 {name=p239 sig_type=std_logic lab=CLKR[8]}
C {lab_pin.sym} -1990 -1480 0 0 {name=p240 sig_type=std_logic lab=vgateN}
C {lab_pin.sym} -1990 -1460 0 0 {name=p241 sig_type=std_logic lab=vgateP}
C {lab_pin.sym} -1990 -1440 0 0 {name=p242 sig_type=std_logic lab=VIN}
C {lab_pin.sym} -1990 -1420 0 0 {name=p243 sig_type=std_logic lab=VIP}
C {/home/yihengfu/openmpw/tools-dev/sample_unit.sym} -1830 -1570 0 0 {name=x28}
C {lab_pin.sym} -1660 -1610 0 0 {name=p244 sig_type=std_logic lab=VCM_1}
C {lab_pin.sym} -1660 -1590 0 0 {name=p245 sig_type=std_logic lab=VCM}
C {lab_pin.sym} -1660 -1570 0 0 {name=p246 sig_type=std_logic lab=VCM_2}
C {lab_pin.sym} -1660 -1550 0 0 {name=p247 sig_type=std_logic lab=agnd}
C {lab_pin.sym} -1660 -1530 0 0 {name=p248 sig_type=std_logic lab=CLKR[8]}
C {lab_pin.sym} -1990 -1610 0 0 {name=p249 sig_type=std_logic lab=vgateN}
C {lab_pin.sym} -1990 -1590 0 0 {name=p250 sig_type=std_logic lab=vgateP}
C {lab_pin.sym} -1990 -1570 0 0 {name=p251 sig_type=std_logic lab=VIN}
C {lab_pin.sym} -1990 -1550 0 0 {name=p252 sig_type=std_logic lab=VIP}
C {/home/yihengfu/openmpw/tools-dev/sample_unit.sym} -1840 -1700 0 0 {name=x29}
C {lab_pin.sym} -1670 -1740 0 0 {name=p253 sig_type=std_logic lab=VCM_1}
C {lab_pin.sym} -1670 -1720 0 0 {name=p254 sig_type=std_logic lab=VCM}
C {lab_pin.sym} -1670 -1700 0 0 {name=p255 sig_type=std_logic lab=VCM_2}
C {lab_pin.sym} -1670 -1680 0 0 {name=p256 sig_type=std_logic lab=agnd}
C {lab_pin.sym} -1670 -1660 0 0 {name=p257 sig_type=std_logic lab=CLKR[8]}
C {lab_pin.sym} -2000 -1740 0 0 {name=p258 sig_type=std_logic lab=vgateN}
C {lab_pin.sym} -2000 -1720 0 0 {name=p259 sig_type=std_logic lab=vgateP}
C {lab_pin.sym} -2000 -1700 0 0 {name=p260 sig_type=std_logic lab=VIN}
C {lab_pin.sym} -2000 -1680 0 0 {name=p261 sig_type=std_logic lab=VIP}
C {/home/yihengfu/openmpw/tools-dev/sample_unit.sym} -1840 -1830 0 0 {name=x30}
C {lab_pin.sym} -1670 -1870 0 0 {name=p262 sig_type=std_logic lab=VCM_1}
C {lab_pin.sym} -1670 -1850 0 0 {name=p263 sig_type=std_logic lab=VCM}
C {lab_pin.sym} -1670 -1830 0 0 {name=p264 sig_type=std_logic lab=VCM_2}
C {lab_pin.sym} -1670 -1810 0 0 {name=p265 sig_type=std_logic lab=agnd}
C {lab_pin.sym} -1670 -1790 0 0 {name=p266 sig_type=std_logic lab=CLKR[8]}
C {lab_pin.sym} -2000 -1870 0 0 {name=p267 sig_type=std_logic lab=vgateN}
C {lab_pin.sym} -2000 -1850 0 0 {name=p268 sig_type=std_logic lab=vgateP}
C {lab_pin.sym} -2000 -1830 0 0 {name=p269 sig_type=std_logic lab=VIN}
C {lab_pin.sym} -2000 -1810 0 0 {name=p270 sig_type=std_logic lab=VIP}
C {/home/yihengfu/openmpw/tools-dev/sample_unit.sym} -1850 -1970 0 0 {name=x31}
C {lab_pin.sym} -1680 -2010 0 0 {name=p271 sig_type=std_logic lab=VCM_1}
C {lab_pin.sym} -1680 -1990 0 0 {name=p272 sig_type=std_logic lab=VCM}
C {lab_pin.sym} -1680 -1970 0 0 {name=p273 sig_type=std_logic lab=VCM_2}
C {lab_pin.sym} -1680 -1950 0 0 {name=p274 sig_type=std_logic lab=agnd}
C {lab_pin.sym} -1680 -1930 0 0 {name=p275 sig_type=std_logic lab=CLKR[8]}
C {lab_pin.sym} -2010 -2010 0 0 {name=p276 sig_type=std_logic lab=vgateN}
C {lab_pin.sym} -2010 -1990 0 0 {name=p277 sig_type=std_logic lab=vgateP}
C {lab_pin.sym} -2010 -1970 0 0 {name=p278 sig_type=std_logic lab=VIN}
C {lab_pin.sym} -2010 -1950 0 0 {name=p279 sig_type=std_logic lab=VIP}
C {/home/yihengfu/openmpw/tools-dev/sample_unit.sym} -1850 -2100 0 0 {name=x32}
C {lab_pin.sym} -1680 -2140 0 0 {name=p280 sig_type=std_logic lab=VCM_1}
C {lab_pin.sym} -1680 -2120 0 0 {name=p281 sig_type=std_logic lab=VCM}
C {lab_pin.sym} -1680 -2100 0 0 {name=p282 sig_type=std_logic lab=VCM_2}
C {lab_pin.sym} -1680 -2080 0 0 {name=p283 sig_type=std_logic lab=agnd}
C {lab_pin.sym} -1680 -2060 0 0 {name=p284 sig_type=std_logic lab=CLKR[8]}
C {lab_pin.sym} -2010 -2140 0 0 {name=p285 sig_type=std_logic lab=vgateN}
C {lab_pin.sym} -2010 -2120 0 0 {name=p286 sig_type=std_logic lab=vgateP}
C {lab_pin.sym} -2010 -2100 0 0 {name=p287 sig_type=std_logic lab=VIN}
C {lab_pin.sym} -2010 -2080 0 0 {name=p288 sig_type=std_logic lab=VIP}
C {ipin.sym} -2320 -330 0 0 {name=p289 lab=VCM_1}
C {opin.sym} -2570 -360 0 0 {name=p290 lab=vgateN}
C {iopin.sym} -2490 -360 0 0 {name=p291 lab=VCM}
C {iopin.sym} -2490 -330 0 0 {name=p292 lab=agnd}
C {iopin.sym} -2490 -300 0 0 {name=p293 lab=CLKR[8:12]}
C {iopin.sym} -2490 -260 0 0 {name=p294 lab=CLK1D}
C {opin.sym} -2570 -330 0 0 {name=p295 lab=vgateP}
C {opin.sym} -2570 -300 0 0 {name=p296 lab=VIN}
C {opin.sym} -2570 -270 0 0 {name=p297 lab=VIP}
C {ipin.sym} -2320 -270 0 0 {name=p298 lab=VCM_2}
